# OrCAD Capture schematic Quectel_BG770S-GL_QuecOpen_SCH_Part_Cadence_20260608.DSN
size A2

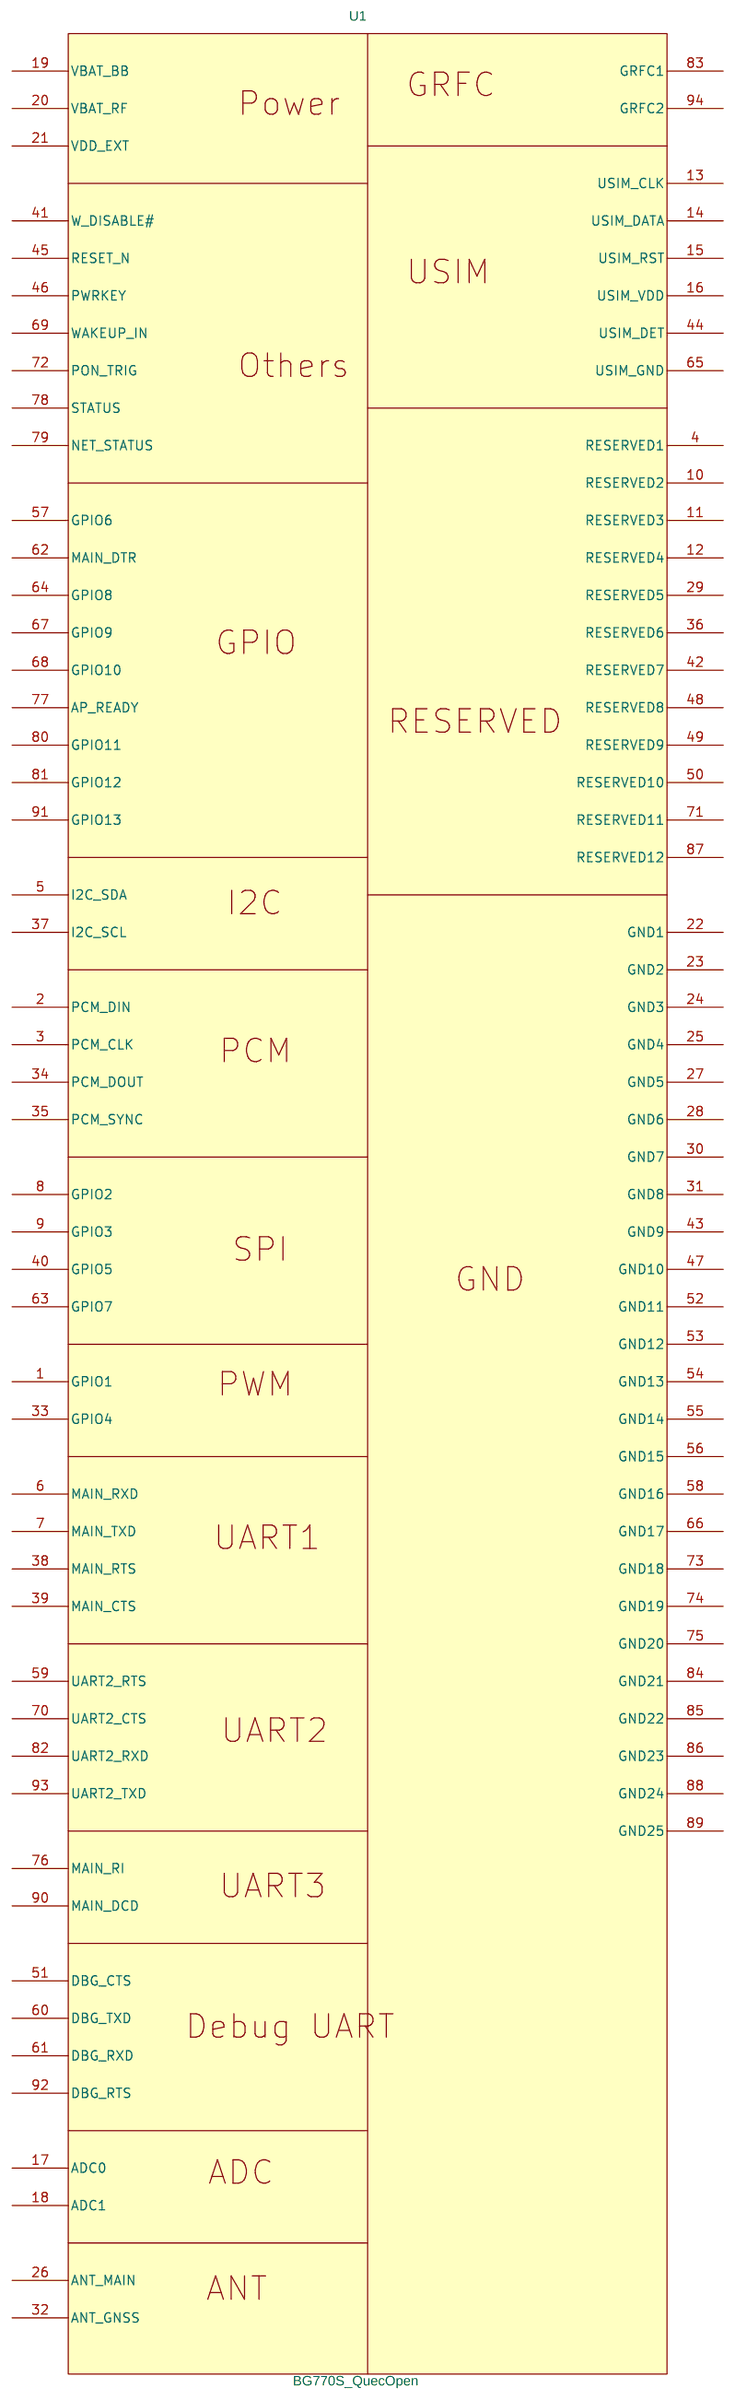
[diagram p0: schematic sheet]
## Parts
U1  BG770S_QuecOpen  [BG770S_QuecOpen]

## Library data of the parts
U1 = BG770S_QuecOpen

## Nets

Not connected (* = marked no-connect by the designer): U1 1(GPIO1) 2(PCM_DIN) 3(PCM_CLK) 4(RESERVED1) 5(I2C_SDA) 6(MAIN_RXD) 7(MAIN_TXD) 8(GPIO2) 9(GPIO3) 10(RESERVED2) 11(RESERVED3) 12(RESERVED4) 13(USIM_CLK) 14(USIM_DATA) 15(USIM_RST) 16(USIM_VDD) 17(ADC0) 18(ADC1) 19(VBAT_BB) 20(VBAT_RF) 21(VDD_EXT) 22(GND1) 23(GND2) 24(GND3) 25(GND4) 26(ANT_MAIN) 27(GND5) 28(GND6) 29(RESERVED5) 30(GND7) 31(GND8) 32(ANT_GNSS) 33(GPIO4) 34(PCM_DOUT) 35(PCM_SYNC) 36(RESERVED6) 37(I2C_SCL) 38(MAIN_RTS) 39(MAIN_CTS) 40(GPIO5) 41(W_DISABLE#) 42(RESERVED7) 43(GND9) 44(USIM_DET) 45(RESET_N) 46(PWRKEY) 47(GND10) 48(RESERVED8) 49(RESERVED9) 50(RESERVED10) 51(DBG_CTS) 52(GND11) 53(GND12) 54(GND13) 55(GND14) 56(GND15) 57(GPIO6) 58(GND16) 59(UART2_RTS) 60(DBG_TXD) 61(DBG_RXD) 62(MAIN_DTR) 63(GPIO7) 64(GPIO8) 65(USIM_GND) 66(GND17) 67(GPIO9) 68(GPIO10) 69(WAKEUP_IN) 70(UART2_CTS) 71(RESERVED11) 72(PON_TRIG) 73(GND18) 74(GND19) 75(GND20) 76(MAIN_RI) 77(AP_READY) 78(STATUS) 79(NET_STATUS) 80(GPIO11) 81(GPIO12) 82(UART2_RXD) 83(GRFC1) 84(GND21) 85(GND22) 86(GND23) 87(RESERVED12) 88(GND24) 89(GND25) 90(MAIN_DCD) 91(GPIO13) 92(DBG_RTS) 93(UART2_TXD) 94(GRFC2)
